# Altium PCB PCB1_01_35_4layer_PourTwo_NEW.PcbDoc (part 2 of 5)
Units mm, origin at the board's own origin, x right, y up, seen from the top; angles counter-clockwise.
Board outline 26.5 x 17 mm, 4 copper layers (Top Layer, Layer 1, Layer 2, Bottom Layer), stack 0.603 mm thick; 0 components, 1 nets, 8 pads, 81 vias.

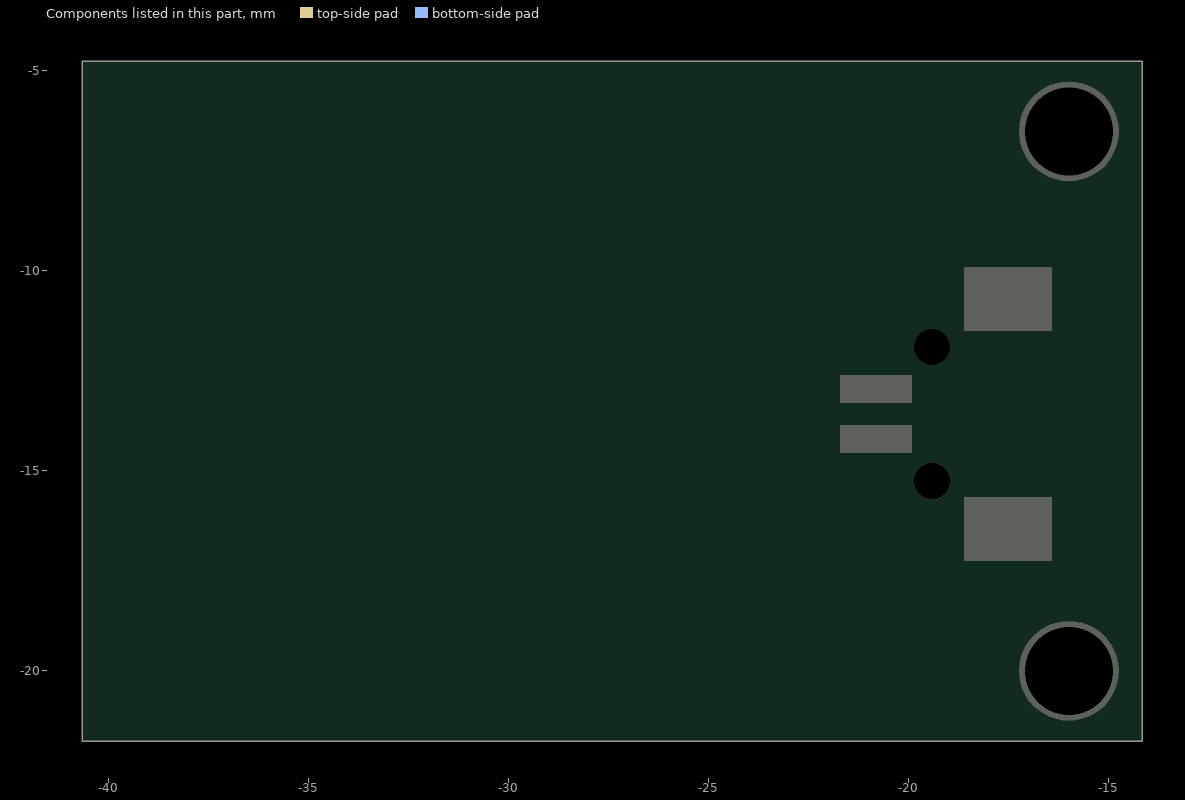
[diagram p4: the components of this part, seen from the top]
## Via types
v1: diameter 0.5, hole 0.3, Top Layer to Bottom Layer, tented both sides, 68 vias
v2: diameter 1, hole 0.5, Top Layer to Bottom Layer, 9 vias
v3: diameter 0.65, hole 0.3, Top Layer to Bottom Layer, 4 vias

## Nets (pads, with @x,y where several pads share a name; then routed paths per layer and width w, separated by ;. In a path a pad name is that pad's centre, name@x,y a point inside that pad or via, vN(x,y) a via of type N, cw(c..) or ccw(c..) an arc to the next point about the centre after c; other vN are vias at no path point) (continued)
copper on no net: | length 3951.7
  Top Layer w0.1: v3(-32.113,-13.739) -32.133,-13.739 -32.71,-13.162 -32.942,-13.162 cw(c-31.927,-13.291) -32.883,-12.927 cw(c-31.835,-13.326) -32.772,-12.709 cw(c-31.779,-13.362) -32.616,-12.519 cw(c-31.776,-13.364) -32.423,-12.364 cw(c-31.806,-13.316) -32.202,-12.252 cw(c-31.832,-13.244) -31.959,-12.193 cw(c-31.832,-13.275) -31.707,-12.193 cw(c-31.843,-13.372) -31.46,-12.249 cw(c-31.859,-13.422) -31.228,-12.355 cw(c-31.849,-13.408) -31.022,-12.508 cw(c-31.802,-13.357) -30.853,-12.702 cw(c-31.77,-13.33) -30.668,-13.185 cw(c-31.907,-13.355) -30.66,-13.448 cw(c-31.926,-13.356) -30.807,-13.954 cw(c-31.835,-13.402) -30.959,-14.173 cw(c-31.801,-13.43) -31.159,-14.352 cw(c-31.861,-13.344) -31.396,-14.481 cw(c-31.892,-13.269) -31.658,-14.557 cw(c-31.896,-13.256) -31.93,-14.578 cw(c-31.898,-13.312) -32.202,-14.541 cw(c-31.919,-13.395) -32.46,-14.444 cw(c-31.912,-13.391) -32.69,-14.288 cw(c-31.841,-13.308) -32.88,-14.084 cw(c-31.789,-13.267) -33.025,-13.842 cw(c-31.797,-13.27) -33.117,-13.575 cw(c-31.868,-13.286) -33.15,-13.293 cw(c-31.954,-13.287) -33.117,-13.01 cw(c-31.893,-13.304) -33.019,-12.741 cw(c-31.799,-13.35) -32.863,-12.497 cw(c-31.769,-13.371) -32.416,-12.129 cw(c-31.819,-13.278) -32.143,-12.025 cw(c-31.838,-13.213) -31.851,-11.986 cw(c-31.837,-13.318) -31.556,-12.016 cw(c-31.856,-13.412) -31.273,-12.109 cw(c-31.865,-13.435) -31.013,-12.259 cw(c-31.834,-13.392) -30.79,-12.46 cw(c-31.763,-13.33) -30.617,-12.706 cw(c-31.747,-13.317) -30.505,-12.989 cw(c-31.863,-13.348) -30.459,-13.291 cw(c-31.943,-13.352) -30.478,-13.598 cw(c-31.945,-13.353) -30.56,-13.895 cw(c-31.877,-13.38) -30.704,-14.169 cw(c-31.796,-13.435) -30.907,-14.405 cw(c-31.821,-13.402) -31.161,-14.588 cw(c-31.879,-13.299) -31.451,-14.711 cw(c-31.898,-13.24) -31.762,-14.771 cw(c-31.897,-13.264) -32.079,-14.767 cw(c-31.908,-13.352) -32.389,-14.693 cw(c-31.92,-13.4) -32.922,-14.342 cw(c-31.803,-13.28) -33.119,-14.085 cw(c-31.789,-13.267) -33.337,-13.474 cw(c-31.917,-13.286) -33.343,-13.146 cw(c-31.967,-13.284) -33.271,-12.824 cw(c-31.848,-13.326) -33.127,-12.526 cw(c-31.765,-13.377) -32.922,-12.263 cw(c-31.755,-13.385) -32.666,-12.047 cw(c-31.794,-13.326) -32.37,-11.889 cw(c-31.834,-13.225) -32.044,-11.801 cw(c-31.837,-13.24) -31.706,-11.792 cw(c-31.848,-13.37) -31.372,-11.859 cw(c-31.87,-13.444) -31.057,-11.995 cw(c-31.862,-13.432) -30.776,-12.194 cw(c-31.802,-13.365) -30.544,-12.448 cw(c-31.716,-13.302) -30.375,-12.75 cw(c-31.792,-13.33) -30.28,-13.085 cw(c-31.915,-13.35) -30.261,-13.435 cw(c-31.953,-13.351) -30.44,-14.113 cw(c-31.835,-13.409) -30.634,-14.408 cw(c-31.773,-13.458) -30.893,-14.652 cw(c-31.848,-13.355) -31.202,-14.831 cw(c-31.894,-13.253) -31.545,-14.94 cw(c-31.9,-13.227) -31.904,-14.976 cw(c-31.902,-13.294) -32.263,-14.937 cw(c-31.927,-13.407) -32.606,-14.818 cw(c-31.931,-13.426) -32.914,-14.622 cw(c-31.842,-13.316) -33.17,-14.36 cw(c-31.769,-13.258) -33.367,-14.048 cw(c-31.771,-13.257) -33.496,-13.701 cw(c-31.858,-13.279) -33.548,-13.334 cw(c-31.978,-13.282) -33.516,-12.963 cw(c-31.924,-13.298) -33.398,-12.608 cw(c-31.799,-13.356) -33.203,-12.287 cw(c-31.742,-13.398) -32.944,-12.011 cw(c-31.762,-13.373) -32.634,-11.794 cw(c-31.814,-13.277) -32.283,-11.649 cw(c-31.836,-13.227) -31.524,-11.616 cw(c-31.863,-13.421) -31.155,-11.727 cw(c-31.867,-13.439) -30.52,-12.164 cw(c-31.754,-13.329) -30.287,-12.476 cw(c-31.709,-13.298) -30.133,-12.835 cw(c-31.852,-13.34) -30.065,-13.222 cw(c-31.962,-13.349) -30.079,-13.616 cw(c-31.974,-13.348) -30.175,-14.001 cw(c-31.893,-13.379) -30.349,-14.357 cw(c-31.784,-13.449) -30.601,-14.666 cw(c-31.795,-13.429) -30.919,-14.909 cw(c-31.873,-13.299) -31.284,-15.075 cw(c-31.902,-13.216) -31.679,-15.162 cw(c-31.901,-13.236) -32.084,-15.167 cw(c-31.913,-13.345) -32.481,-15.084 cw(c-31.951,-13.464) -32.851,-14.912 cw(c-31.896,-13.381) -33.171,-14.657 cw(c-31.795,-13.279) -33.43,-14.338 cw(c-31.763,-13.254) -33.726,-13.57 cw(c-31.92,-13.282) -33.745,-13.156 cw(c-32.009,-13.278) -33.666,-12.746 cw(c-31.866,-13.324) -33.494,-12.364 cw(c-31.755,-13.388) -33.244,-12.026 cw(c-31.734,-13.406) -32.929,-11.745 cw(c-31.78,-13.339) -32.561,-11.536 cw(c-31.834,-13.213) -32.155,-11.414 cw(c-31.842,-13.198) -31.729,-11.39 cw(c-31.852,-13.361) -31.308,-11.463 cw(c-31.88,-13.463) -30.909,-11.623 cw(c-31.876,-13.459) -30.55,-11.863 cw(c-31.806,-13.377) -30.25,-12.174 cw(c-31.695,-13.291) -30.027,-12.546 cw(c-31.762,-13.315) -29.898,-12.961 cw(c-31.917,-13.346) -29.862,-13.397 cw(c-31.982,-13.347) -30.063,-14.249 cw(c-31.84,-13.412) -30.294,-14.624 cw(c-31.788,-13.441) -30.986,-15.17 cw(c-31.893,-13.242) -31.408,-15.317 cw(c-31.902,-13.228) -32.3,-15.337 cw(c-31.933,-13.412) -32.729,-15.202 cw(c-31.931,-13.423) -33.118,-14.97 cw(c-31.839,-13.302) -33.447,-14.656 cw(c-31.796,-13.262) -33.874,-13.854 cw(c-31.942,-13.305) -33.949,-13.401 cw(c-31.932,-13.311) -33.917,-12.941 cw(c-31.792,-13.336) -33.784,-12.498 cw(c-31.768,-13.341) -33.255,-11.74 cw(c-31.888,-13.218) -32.879,-11.465 cw(c-31.856,-13.283) -32.447,-11.283 cw(c-31.818,-13.407) -31.985,-11.198 cw(c-31.815,-13.433) -31.513,-11.212 cw(c-31.802,-13.347) -31.055,-11.326 cw(c-31.781,-13.274) -30.268,-11.848 cw(c-31.91,-13.409) -29.977,-12.228 cw(c-31.91,-13.411) -29.772,-12.661 cw(c-31.809,-13.377) -29.664,-13.129 cw(c-31.714,-13.363) -29.665,-13.611 cw(c-31.866,-13.345) -29.775,-14.082 cw(c-31.956,-13.315) -29.984,-14.52 cw(c-31.934,-13.329) -30.281,-14.907 cw(c-31.846,-13.415) -30.655,-15.219 cw(c-31.819,-13.447) -31.092,-15.439 cw(c-31.874,-13.298) -31.57,-15.557 cw(c-31.884,-13.246) -32.549,-15.482 cw(c-31.93,-13.41) -33.005,-15.286 cw(c-31.912,-13.39) -33.405,-14.991 cw(c-31.811,-13.28) -33.731,-14.613 cw(c-31.801,-13.267) -34.116,-13.693 cw(c-31.985,-13.305) -34.148,-13.191 cw(c-31.893,-13.314) -34.064,-12.693 cw(c-31.763,-13.35) -33.874,-12.223 cw(c-31.744,-13.358) -33.588,-11.801 cw(c-31.819,-13.293) -33.219,-11.451 cw(c-31.867,-13.243) -32.289,-11.038 cw(c-31.819,-13.435) -31.776,-10.993 cw(c-31.817,-13.428) -31.264,-11.056 cw(c-31.789,-13.312) -30.777,-11.228 cw(c-31.752,-13.229) -30.34,-11.508 cw(c-31.858,-13.358) -29.976,-11.88 cw(c-31.932,-13.418) -29.698,-12.323 cw(c-31.9,-13.404) -29.519,-12.815 cw(c-31.767,-13.373) -29.451,-13.335 cw(c-31.739,-13.366) -29.504,-13.859 cw(c-31.903,-13.331) -29.673,-14.36 cw(c-31.947,-13.315) -30.305,-15.204 cw(c-31.821,-13.456) -30.745,-15.505 cw(c-31.836,-13.412) -31.244,-15.696 cw(c-31.877,-13.262) -31.774,-15.775 cw(c-31.881,-13.218) -32.311,-15.741 cw(c-31.897,-13.305) -32.829,-15.594 cw(c-31.955,-13.447) -33.302,-15.333 cw(c-31.886,-13.357) -33.704,-14.97 cw(c-31.782,-13.263) -34.021,-14.528 cw(c-31.77,-13.254) -34.238,-14.027 cw(c-31.878,-13.286) -34.343,-13.491 cw(c-31.937,-13.301) -34.181,-12.413 cw(c-31.74,-13.366) -33.927,-11.923 cw(c-31.751,-13.356) -33.576,-11.496 cw(c-31.843,-13.261) -33.14,-11.155 cw(c-31.891,-13.192) -32.635,-10.922 cw(c-31.834,-13.362) -32.09,-10.806 cw(c-31.823,-13.457) -31.531,-10.809 cw(c-31.816,-13.413) -30.983,-10.929 cw(c-31.767,-13.271) -30.475,-11.167 cw(c-31.767,-13.257) -30.033,-11.516 cw(c-31.89,-13.383) -29.677,-11.955 cw(c-31.921,-13.408) -29.278,-13.011 cw(c-31.716,-13.374) -29.259,-13.58 cw(c-31.782,-13.362) -29.372,-14.139 cw(c-31.936,-13.313) -29.605,-14.663 cw(c-31.971,-13.296) -29.943,-15.128 cw(c-31.897,-13.364) -30.373,-15.51 cw(c-31.804,-13.496) -30.88,-15.787 cw(c-31.851,-13.37) -31.437,-15.942 cw(c-31.876,-13.228) -32.017,-15.973 cw(c-31.877,-13.22) -32.592,-15.883 cw(c-31.911,-13.341) -33.135,-15.67 cw(c-31.971,-13.459) -33.617,-15.339 cw(c-31.853,-13.325) -34.013,-14.907 cw(c-31.756,-13.252) -34.309,-14.398 cw(c-31.779,-13.26) -34.493,-13.838 cw(c-31.923,-13.29) -34.55,-13.25 cw(c-31.995,-13.294) -34.471,-12.663 cw(c-31.81,-13.34) -34.263,-12.106 cw(c-31.74,-13.371) -33.52,-11.181 cw(c-31.869,-13.217) -33.016,-10.859 cw(c-31.873,-13.227) -32.449,-10.662 cw(c-31.831,-13.405) -31.851,-10.593 cw(c-31.825,-13.435) -30.674,-10.837 cw(c-31.738,-13.227) -30.152,-11.146 cw(c-31.797,-13.294) -29.714,-11.567 cw(c-31.924,-13.402) -29.377,-12.075 cw(c-31.953,-13.419) -29.153,-12.644 cw(c-31.843,-13.39) -29.054,-13.248 ; -29.056,-16.506 ccw(c-31.858,-13.398) -28.441,-15.813 ccw(c-31.984,-13.306) -27.99,-15.006 ccw(c-31.93,-13.326) -27.722,-14.122 ccw(c-31.697,-13.368) -27.654,-13.203 ccw(c-31.802,-13.38) -27.795,-12.294 ccw(c-31.956,-13.419) -28.128,-11.438 ccw(c-31.911,-13.393) -28.634,-10.673 ccw(c-31.732,-13.242) -29.294,-10.039 ccw(c-31.782,-13.321) -30.079,-9.572 ccw(c-31.851,-13.467) -30.945,-9.284 ccw(c-31.845,-13.421) -31.851,-9.188 ccw(c-31.847,-13.186) -32.754,-9.292 ccw(c-31.83,-13.207) -33.607,-9.598 ccw(c-31.729,-13.418) -34.373,-10.082 ccw(c-31.702,-13.457) -35.019,-10.715 ccw(c-31.839,-13.347) -35.515,-11.469 ccw(c-32.084,-13.222) -35.828,-12.313 ccw(c-31.893,-13.263) -35.941,-13.205 ccw(c-31.691,-13.268) -35.86,-14.099 ccw(c-31.692,-13.272) -35.593,-14.956 ccw(c-31.885,-13.358) -35.15,-15.733 ccw(c-32.065,-13.483) -34.543,-16.388 ccw(c-31.903,-13.292) -33.806,-16.889 ccw(c-31.823,-13.147) -32.979,-17.221 ccw(c-31.833,-13.196) -32.103,-17.372 ccw(c-31.847,-13.437) -31.218,-17.33 ccw(c-31.837,-13.556) -30.367,-17.086 ccw(c-31.972,-13.25) -28.926,-16.081 ccw(c-31.932,-13.276) -28.397,-15.376 ccw(c-31.704,-13.409) -28.037,-14.574 ccw(c-31.708,-13.42) -27.871,-13.713 ccw(c-32.004,-13.401) -28.108,-11.987 ccw(c-31.9,-13.358) -28.492,-11.202 ccw(c-31.668,-13.209) -29.04,-10.525 ccw(c-31.743,-13.299) -29.727,-9.992 ccw(c-31.859,-13.483) -30.512,-9.62 ccw(c-31.873,-13.514) -31.357,-9.422 ccw(c-31.853,-13.338) -32.222,-9.408 ccw(c-31.876,-13.083) -33.067,-9.589 ccw(c-31.807,-13.275) -33.847,-9.956 ccw(c-31.711,-13.435) -34.529,-10.482 ccw(c-31.723,-13.427) -35.086,-11.138 ccw(c-31.899,-13.31) -35.487,-11.896 ccw(c-32.074,-13.236) -35.705,-12.724 ccw(c-31.83,-13.27) -35.731,-13.578 ccw(c-31.681,-13.261) -35.576,-14.417 ccw(c-31.736,-13.281) -35.248,-15.204 ccw(c-31.945,-13.397) -34.759,-15.899 ccw(c-32.017,-13.448) -34.124,-16.462 ccw(c-31.842,-13.188) -32.571,-17.112 ccw(c-31.846,-13.248) -31.729,-17.177 ccw(c-31.836,-13.507) -30.895,-17.056 ccw(c-31.854,-13.482) -30.113,-16.748 ccw(c-31.96,-13.28) -29.419,-16.276 ccw(c-32,-13.228) -28.839,-15.67 ccw(c-31.885,-13.313) -28.402,-14.957 ccw(c-31.646,-13.425) -28.136,-14.166 ccw(c-31.78,-13.404) -28.058,-13.337 ccw(c-31.982,-13.405) -28.16,-12.511 ccw(c-32.003,-13.408) -28.433,-11.726 ccw(c-31.732,-13.261) -29.447,-10.43 ccw(c-31.785,-13.351) -30.144,-9.989 ccw(c-31.862,-13.503) -30.919,-9.707 ccw(c-31.859,-13.48) -31.734,-9.593 ccw(c-31.854,-13.27) -32.552,-9.658 ccw(c-31.879,-13.11) -33.333,-9.907 ccw(c-31.741,-13.395) -34.635,-10.881 ccw(c-31.755,-13.395) -35.102,-11.549 ccw(c-31.961,-13.283) -35.412,-12.3 ccw(c-32.014,-13.258) -35.541,-13.102 ccw(c-31.722,-13.266) -35.27,-14.689 ccw(c-31.787,-13.298) -34.891,-15.403 ccw(c-31.995,-13.441) -34.366,-16.013 ccw(c-31.965,-13.395) -33.716,-16.486 ccw(c-31.859,-13.211) -32.979,-16.805 ccw(c-31.841,-13.161) -32.193,-16.962 ccw(c-31.852,-13.307) -31.393,-16.95 ccw(c-31.82,-13.555) -30.618,-16.758 ccw(c-31.878,-13.417) -29.91,-16.396 ccw(c-31.979,-13.26) -29.296,-15.891 ccw(c-31.984,-13.251) -28.802,-15.268 ccw(c-31.722,-13.399) -28.277,-13.787 ccw(c-31.842,-13.398) -28.278,-12.999 ccw(c-31.996,-13.413) -28.447,-12.229 ccw(c-31.966,-13.4) -28.773,-11.514 ccw(c-31.788,-13.292) -29.244,-10.887 ccw(c-31.687,-13.206) -29.845,-10.386 ccw(c-31.845,-13.46) -31.296,-9.834 ccw(c-31.849,-13.435) -32.074,-9.799 ccw(c-31.865,-13.206) -32.839,-9.935 ccw(c-31.864,-13.174) -33.55,-10.241 ccw(c-31.725,-13.407) -34.691,-11.272 ccw(c-31.797,-13.362) -35.072,-11.942 ccw(c-32.02,-13.267) -35.294,-12.678 ccw(c-31.945,-13.272) -35.342,-13.443 ccw(c-31.748,-13.263) -35.223,-14.2 ccw(c-31.708,-13.255) -34.948,-14.914 ccw(c-31.838,-13.325) -34.528,-15.551 ccw(c-32.019,-13.474) -33.978,-16.077 ccw(c-31.926,-13.343) -33.324,-16.462 ccw(c-31.854,-13.188) -32.603,-16.698 ccw(c-31.852,-13.189) -31.85,-16.778 ccw(c-31.849,-13.368) -31.099,-16.694 ccw(c-31.811,-13.552) -30.389,-16.443 ccw(c-31.904,-13.365) -29.755,-16.039 ccw(c-31.99,-13.255) -29.222,-15.51 ccw(c-31.956,-13.279) -28.813,-14.882 ccw(c-31.774,-13.37) -28.55,-14.182 ccw(c-31.674,-13.403) -28.454,-13.443 ccw(c-31.954,-13.405) -28.752,-11.994 ccw(c-31.923,-13.384) -29.12,-11.35 ccw(c-31.742,-13.251) -29.62,-10.805 ccw(c-31.732,-13.254) -30.23,-10.39 ccw(c-31.845,-13.476) -31.641,-9.999 ccw(c-31.844,-13.383) -32.374,-10.034 ccw(c-31.882,-13.152) -33.079,-10.232 ccw(c-31.84,-13.236) -33.718,-10.584 ccw(c-31.736,-13.386) -34.266,-11.066 ccw(c-31.716,-13.408) -34.699,-11.651 ccw(c-31.846,-13.334) -34.997,-12.313 ccw(c-32.052,-13.266) -35.138,-13.024 ccw(c-31.885,-13.276) -35.114,-13.746 ccw(c-31.73,-13.256) -34.936,-14.445 ccw(c-31.739,-13.262) -34.615,-15.091 ccw(c-31.887,-13.359) -34.166,-15.65 ccw(c-32.005,-13.471) -33.601,-16.092 ccw(c-31.899,-13.297) -32.954,-16.395 ccw(c-31.857,-13.179) -32.257,-16.553 ccw(c-31.86,-13.228) -31.545,-16.562 ccw(c-31.839,-13.427) -30.849,-16.416 ccw(c-31.823,-13.503) -30.207,-16.116 ccw(c-31.964,-13.284) -29.196,-15.139 ccw(c-31.92,-13.307) -28.868,-14.515 ccw(c-31.717,-13.385) -28.685,-13.836 ccw(c-31.737,-13.391) -28.663,-13.136 ccw(c-31.926,-13.405) -28.795,-12.448 ccw(c-31.98,-13.419) -29.068,-11.805 ccw(c-31.877,-13.36) -29.47,-11.235 ccw(c-31.711,-13.212) -29.987,-10.771 ccw(c-31.769,-13.305) -30.595,-10.438 ccw(c-31.834,-13.459) -31.26,-10.245 ccw(c-31.84,-13.477) -31.95,-10.195 ccw(c-31.862,-13.22) -33.273,-10.543 ccw(c-31.813,-13.286) -33.839,-10.929 ccw(c-31.723,-13.394) -34.309,-11.428 ccw(c-31.739,-13.385) -34.663,-12.013 ccw(c-31.898,-13.312) -34.882,-12.658 ccw(c-32.032,-13.278) -34.948,-13.334 ccw(c-31.836,-13.274) -34.862,-14.007 ccw(c-31.727,-13.25) -34.634,-14.645 ccw(c-31.776,-13.276) -34.279,-15.22 ccw(c-31.929,-13.397) -33.809,-15.702 ccw(c-31.968,-13.432) -33.241,-16.062 ccw(c-31.867,-13.214) -31.946,-16.376 ccw(c-31.863,-13.274) -31.28,-16.322 ccw(c-31.823,-13.479) -30.645,-16.122 ccw(c-31.846,-13.446) -30.073,-15.783 ccw(c-31.951,-13.306) -29.59,-15.329 ccw(c-31.983,-13.275) -29.214,-14.784 ccw(c-31.876,-13.331) -28.963,-14.173 ccw(c-31.675,-13.389) -28.855,-13.524 ccw(c-31.795,-13.388) -28.898,-12.869 ccw(c-31.946,-13.413) -29.081,-12.239 ccw(c-31.955,-13.414) -29.391,-11.663 ccw(c-31.757,-13.263) -30.341,-10.783 ccw(c-31.795,-13.35) -30.937,-10.527 ccw(c-31.833,-13.471) -31.573,-10.404 ccw(c-31.833,-13.444) -32.22,-10.418 ccw(c-31.857,-13.275) -32.846,-10.57 ccw(c-31.89,-13.166) -33.42,-10.861 ccw(c-31.751,-13.366) -34.307,-11.776 ccw(c-31.771,-13.361) -34.586,-12.351 ccw(c-31.95,-13.299) -34.732,-12.971 ccw(c-31.977,-13.287) -34.731,-13.606 ccw(c-31.759,-13.259) -34.325,-14.799 ccw(c-31.815,-13.298) -33.944,-15.302 ccw(c-31.96,-13.436) -33.463,-15.708 ccw(c-31.934,-13.384) -32.904,-15.991 ccw(c-31.877,-13.234) -32.297,-16.146 ccw(c-31.87,-13.201) -31.672,-16.17 ccw(c-31.86,-13.322) -31.058,-16.061 ccw(c-31.806,-13.508) -30.486,-15.818 ccw(c-31.872,-13.399) -29.986,-15.452 ccw(c-31.965,-13.296) -29.577,-14.988 ccw(c-31.964,-13.294) -29.274,-14.449 ccw(c-31.74,-13.377) -29.054,-13.248 ; -29.056,-16.506 cw(c-31.775,-13.48) -29.812,-17.043 cw(c-31.892,-13.271) -30.669,-17.401 cw(c-31.913,-13.211) -31.585,-17.57 cw(c-31.904,-13.363) -32.516,-17.537 cw(c-31.916,-13.491) -33.418,-17.296 cw(c-31.829,-13.265) -34.246,-16.861 cw(c-31.793,-13.207) -34.965,-16.258 cw(c-31.902,-13.308) -35.537,-15.515 cw(c-32.018,-13.386) -35.928,-14.66 cw(c-31.786,-13.309) -36.122,-13.739 cw(c-31.775,-13.298) -35.906,-11.875 cw(c-32.001,-13.235) -35.495,-11.023 cw(c-31.793,-13.366) -34.904,-10.281 cw(c-31.771,-13.373) -33.32,-9.253 cw(c-31.87,-13.15) -32.395,-9.025 cw(c-31.838,-13.395) -31.442,-9.008 cw(c-31.831,-13.424) -29.628,-9.577 cw(c-31.717,-13.199) -28.858,-10.148 cw(c-31.886,-13.38) -28.233,-10.876 cw(c-31.911,-13.408) -27.51,-12.648 cw(c-31.656,-13.352) -27.459,-13.611 cw(c-31.903,-13.337) -27.623,-14.563 cw(c-31.949,-13.333) -28.534,-16.26 cw(c-31.738,-13.499) -29.247,-16.917 cw(c-31.883,-13.3) -30.091,-17.401 cw(c-31.912,-13.254) -31.991,-17.783 cw(c-31.906,-13.53) -32.958,-17.651 cw(c-31.845,-13.292) -33.874,-17.308 cw(c-31.825,-13.233) -35.389,-16.079 cw(c-31.94,-13.355) -36.229,-14.314 cw(c-31.752,-13.29) -36.248,-12.352 cw(c-31.928,-13.276) -35.418,-10.568 cw(c-31.751,-13.385) -33.909,-9.295 cw(c-31.856,-13.233) -31.994,-8.795 cw(c-31.827,-13.447) -30.039,-9.149 cw(c-31.772,-13.261) -28.422,-10.312 cw(c-31.925,-13.426) -27.443,-12.055 cw(c-31.738,-13.349) -27.308,-14.054 cw(c-31.971,-13.334) -28.032,-15.931 cw(c-31.787,-13.434) -29.495,-17.317 cw(c-31.927,-13.239) -31.414,-17.96 cw(c-31.888,-13.541) -32.434,-17.951 cw(c-31.858,-13.329) -33.427,-17.715 cw(c-31.823,-13.212) -35.155,-16.639 cw(c-32.032,-13.435) -35.803,-15.843 cw(c-31.856,-13.328) -36.257,-14.922 cw(c-31.735,-13.278) -36.531,-12.892 cw(c-32.041,-13.258) -36.329,-11.88 cw(c-31.854,-13.324) -35.906,-10.937 cw(c-31.731,-13.39) -34.508,-9.424 cw(c-31.911,-13.141) -33.595,-8.93 cw(c-31.846,-13.319) -32.593,-8.654 cw(c-31.816,-13.487) -31.552,-8.599 cw(c-31.809,-13.412) -30.523,-8.767 cw(c-31.74,-13.168) -29.555,-9.159 cw(c-31.832,-13.323) -28.698,-9.759 cw(c-31.946,-13.457) -27.989,-10.53 cw(c-31.888,-13.419) -27.459,-11.435 cw(c-31.655,-13.316) -27.142,-12.437 cw(c-31.822,-13.341) -27.058,-13.485 cw(c-32.005,-13.339) -27.201,-14.529 cw(c-31.944,-13.357) -27.563,-15.52 cw(c-31.715,-13.472) -28.135,-16.408 cw(c-31.833,-13.365) -28.894,-17.146 cw(c-31.951,-13.218) -29.795,-17.704 cw(c-31.929,-13.273) -30.795,-18.059 cw(c-31.872,-13.522) -31.85,-18.185 cw(c-31.863,-13.375) -32.908,-18.07 cw(c-31.824,-13.184) -33.919,-17.729 cw(c-31.849,-13.231) -34.835,-17.181 cw(c-32.005,-13.434) -35.609,-16.444 cw(c-31.896,-13.355) -36.198,-15.551 cw(c-31.718,-13.26) -36.582,-14.549 cw(c-31.765,-13.269) -36.744,-13.488 cw(c-32.02,-13.278) -36.669,-12.416 cw(c-31.902,-13.31) -36.355,-11.387 cw(c-31.71,-13.39) -35.825,-10.447 cw(c-31.742,-13.363) -35.106,-9.641 cw(c-31.911,-13.172) -34.228,-9.011 cw(c-31.867,-13.273) -33.228,-8.595 cw(c-31.804,-13.477) -32.16,-8.404 cw(c-31.803,-13.441) -31.075,-8.444 cw(c-31.764,-13.191) -30.024,-8.722 cw(c-31.809,-13.276) -29.061,-9.229 cw(c-31.93,-13.46) -28.229,-9.934 cw(c-31.906,-13.442) -27.564,-10.801 cw(c-31.69,-13.313) -27.105,-11.793 cw(c-31.771,-13.328) -26.881,-12.865 cw(c-31.996,-13.352) -26.894,-13.962 cw(c-31.973,-13.359) -27.14,-15.032 cw(c-31.738,-13.443) -27.614,-16.024 cw(c-31.789,-13.397) -28.3,-16.884 cw(c-31.955,-13.235) -29.159,-17.577 cw(c-31.949,-13.252) -30.146,-18.073 cw(c-31.864,-13.484) -31.218,-18.341 cw(c-31.859,-13.43) -32.325,-18.361 cw(c-31.84,-13.193) -33.412,-18.14 cw(c-31.847,-13.203) -34.429,-17.692 cw(c-31.971,-13.414) -35.324,-17.034 cw(c-31.936,-13.394) -36.049,-16.189 cw(c-31.736,-13.255) -36.574,-15.205 cw(c-31.742,-13.253) -36.879,-14.13 cw(c-31.981,-13.291) -36.943,-13.015 cw(c-31.959,-13.305) -36.753,-11.912 cw(c-31.718,-13.372) -36.327,-10.874 cw(c-31.715,-13.37) -35.69,-9.949 cw(c-31.895,-13.211) -34.866,-9.185 cw(c-31.9,-13.225) -33.89,-8.625 cw(c-31.796,-13.458) -32.813,-8.29 cw(c-31.791,-13.466) -31.688,-8.191 cw(c-31.783,-13.229) -30.568,-8.339 cw(c-31.794,-13.219) -29.508,-8.737 cw(c-31.91,-13.453) -28.559,-9.356 cw(c-31.917,-13.467) -27.762,-10.164 cw(c-31.732,-13.324) -27.158,-11.127 cw(c-31.717,-13.302) -26.787,-12.202 cw(c-31.976,-13.363) -26.659,-13.335 cw(c-31.998,-13.367) -26.774,-14.471 cw(c-31.774,-13.417) -27.133,-15.555 cw(c-31.733,-13.422) -27.728,-16.532 cw(c-31.95,-13.258) -28.523,-17.357 cw(c-31.971,-13.238) -29.477,-17.995 cw(c-31.868,-13.44) -30.547,-18.412 cw(c-31.842,-13.49) -31.685,-18.577 cw(c-31.854,-13.213) -32.834,-18.49 cw(c-31.851,-13.178) -33.94,-18.16 cw(c-31.94,-13.382) -34.948,-17.598 cw(c-31.971,-13.446) -35.806,-16.823 cw(c-31.761,-13.257) -36.474,-15.877 cw(c-31.726,-13.233) -36.927,-14.809 cw(c-31.937,-13.294) -37.138,-13.668 cw(c-32.022,-13.312) -37.087,-12.506 cw(c-31.737,-13.354) -36.782,-11.383 cw(c-31.69,-13.368) -36.245,-10.348 cw(c-31.868,-13.247) -35.496,-9.453 cw(c-31.947,-13.181) -34.564,-8.748 cw(c-31.795,-13.431) -33.498,-8.264 cw(c-31.774,-13.483) -32.352,-8.017 cw(c-31.793,-13.273) -31.18,-8.023 cw(c-31.79,-13.155) -30.036,-8.294 cw(c-31.888,-13.435) -28.979,-8.81 cw(c-31.919,-13.49) -28.053,-9.539 cw(c-31.771,-13.344) -27.307,-10.451 cw(c-31.666,-13.264) -26.784,-11.51 cw(c-31.948,-13.368) -26.505,-12.66 cw(c-32.016,-13.381) -26.478,-13.844 cw(c-31.814,-13.401) -26.706,-15.007 cw(c-31.671,-13.436) -27.19,-16.09 cw(c-31.934,-13.283) -27.903,-17.042 cw(c-31.993,-13.234) -28.802,-17.822 cw(c-31.882,-13.399) -29.849,-18.391 cw(c-31.813,-13.545) -30.999,-18.71 cw(c-31.863,-13.242) -32.192,-18.768 cw(c-31.862,-13.158) -33.373,-18.571 cw(c-31.917,-13.344) -34.484,-18.124 cw(c-31.994,-13.503) -35.468,-17.439 cw(c-31.79,-13.27) -36.277,-16.551 cw(c-31.789,-13.253) -37.247,-14.364 cw(c-32.078,-13.332) -37.346,-13.163 cw(c-31.767,-13.34) -37.178,-11.968 cw(c-31.744,-13.333) -36.105,-9.815 cw(c-31.997,-13.152) -35.238,-8.969 cw(c-31.804,-13.398) -34.204,-8.333 cw(c-31.78,-13.421) -31.85,-7.786 cw(c-31.801,-13.1) -30.639,-7.914 cw(c-31.868,-13.406) -29.485,-8.308 cw(c-31.875,-13.448) -27.553,-9.78 cw(c-31.633,-13.221) -26.877,-10.8 cw(c-31.911,-13.364) -26.442,-11.946 cw(c-31.958,-13.388) -26.345,-14.386 cw(c-31.62,-13.433) -26.701,-15.563 cw(c-31.906,-13.309) -27.31,-16.633 cw(c-31.963,-13.282) -29.137,-18.271 cw(c-31.778,-13.579) -30.277,-18.75 cw(c-31.865,-13.282) -31.496,-18.964 cw(c-31.88,-13.21) -33.935,-18.598 cw(c-31.927,-13.418) -35.982,-17.215 cw(c-31.769,-13.231) -37.261,-15.092 cw(c-31.97,-13.329) -37.502,-12.622 cw(c-31.714,-13.333) -36.677,-10.272 cw(c-31.927,-13.235) -34.918,-8.502 cw(c-31.761,-13.443) -32.57,-7.636 cw(c-31.821,-13.206) -30.074,-7.864 cw(c-31.88,-13.476) -27.899,-9.128 cw(c-31.726,-13.272) -26.476,-11.207 cw(c-31.982,-13.403) -26.062,-13.7 cw(c-31.717,-13.393) -26.76,-16.133 cw(c-31.989,-13.274) -28.426,-18.05 cw(c-31.752,-13.578) -29.533,-18.691 cw(c-31.855,-13.329) -30.756,-19.068 cw(c-31.891,-13.186) -33.307,-19.007 cw(c-31.975,-13.563) -34.513,-18.56 cw(c-31.853,-13.334) -35.588,-17.854 cw(c-31.758,-13.207) -37.174,-15.839 cw(c-32.104,-13.382) -37.601,-14.621 cw(c-31.859,-13.333) -37.743,-13.336 cw(c-31.69,-13.326) -37.199,-10.817 cw(c-32.044,-13.171) -36.529,-9.707 cw(c-31.86,-13.322) -35.625,-8.774 cw(c-31.74,-13.456) -33.327,-7.582 cw(c-31.846,-13.085) -32.038,-7.39 cw(c-31.846,-13.311) -30.737,-7.491 cw(c-31.883,-13.525) -29.485,-7.871 cw(c-31.844,-13.444) -28.343,-8.508 cw(c-31.657,-13.184) -27.368,-9.383 cw(c-31.823,-13.318) -26.613,-10.455 cw(c-32.018,-13.43) -26.106,-11.667 cw(c-31.936,-13.41) -25.868,-12.959 cw(c-31.616,-13.388) -25.92,-14.274 cw(c-31.812,-13.348) -26.267,-15.545 cw(c-32.029,-13.266) -26.88,-16.714 cw(c-31.968,-13.312) -27.728,-17.726 cw(c-31.747,-13.546) -28.78,-18.527 cw(c-31.833,-13.381) -29.986,-19.073 cw(c-31.91,-13.155) -31.283,-19.346 cw(c-31.908,-13.224) -32.61,-19.338 cw(c-31.947,-13.543) -33.903,-19.037 cw(c-31.879,-13.386) -35.098,-18.453 cw(c-31.75,-13.176) -36.14,-17.624 cw(c-31.797,-13.217) -36.983,-16.591 cw(c-32.066,-13.389) -37.579,-15.398 cw(c-31.916,-13.348) -37.892,-14.099 cw(c-31.665,-13.312) -37.917,-12.761 cw(c-31.719,-13.303) -37.657,-11.447 cw(c-32.023,-13.205) -37.116,-10.221 cw(c-31.91,-13.287) -36.311,-9.148 cw(c-31.717,-13.463) -35.291,-8.272 cw(c-31.74,-13.421) -34.108,-7.632 cw(c-31.857,-13.127) -32.812,-7.266 cw(c-31.851,-13.249) -31.466,-7.201 cw(c-31.864,-13.517) -30.135,-7.43 cw(c-31.849,-13.48) -28.881,-7.936 cw(c-31.698,-13.204) -27.768,-8.705 cw(c-31.778,-13.274) -26.856,-9.705 cw(c-31.998,-13.439) -26.181,-10.882 cw(c-31.967,-13.43) -25.771,-12.176 cw(c-31.661,-13.371) -25.653,-13.53 cw(c-31.748,-13.354) -25.843,-14.877 cw(c-32.022,-13.287) -26.322,-16.152 cw(c-32.002,-13.302) -27.061,-17.299 cw(c-31.764,-13.499) -28.033,-18.257 cw(c-31.795,-13.435) -29.197,-18.972 cw(c-31.921,-13.174) -30.491,-19.418 cw(c-31.922,-13.192) -31.852,-19.58 cw(c-31.922,-13.498) -33.216,-19.441 cw(c-31.896,-13.451) -34.514,-18.998 cw(c-31.773,-13.181) -35.688,-18.282 cw(c-31.782,-13.186) -36.685,-17.333 cw(c-32.014,-13.378) -37.451,-16.188 cw(c-31.979,-13.377) -37.939,-14.899 cw(c-31.685,-13.298) -38.137,-13.532 cw(c-31.687,-13.294) -38.039,-12.153 cw(c-31.979,-13.238) -37.644,-10.828 cw(c-31.973,-13.258) -36.96,-9.624 cw(c-31.72,-13.438) -36.028,-8.596 cw(c-31.712,-13.439) -34.898,-7.789 cw(c-31.853,-13.182) -33.62,-7.246 cw(c-31.87,-13.181) -32.25,-7.005 cw(c-31.847,-13.498) -30.858,-7.068 cw(c-31.845,-13.513) -29.51,-7.426 cw(c-31.738,-13.243) -28.271,-8.067 cw(c-31.737,-13.214) -27.207,-8.973 cw(c-31.971,-13.438) -26.365,-10.091 cw(c-31.988,-13.454) -25.779,-11.363 cw(c-31.717,-13.366) -25.482,-12.733 cw(c-31.674,-13.346) -25.502,-14.136 cw(c-32.003,-13.308) -25.828,-15.503 cw(c-32.034,-13.302) -26.438,-16.772 cw(c-31.797,-13.453) -27.308,-17.878 cw(c-31.741,-13.487) -28.406,-18.761 cw(c-31.924,-13.204) -29.673,-19.384 cw(c-31.942,-13.168) -31.045,-19.724 cw(c-31.908,-13.443) -32.458,-19.759 cw(c-31.901,-13.526) -33.845,-19.475 cw(c-31.797,-13.199) -35.137,-18.893 cw(c-31.777,-13.155) -36.279,-18.049 cw(c-31.964,-13.353) -37.211,-16.978 cw(c-32.04,-13.422) -37.878,-15.722 cw(c-31.716,-13.291) -38.256,-14.35 cw(c-31.662,-13.278) -38.333,-12.926 cw(c-31.928,-13.26) -38.101,-11.519 cw(c-32.048,-13.24) -37.557,-10.199 cw(c-31.735,-13.409) -36.736,-9.028 cw(c-31.684,-13.447) -35.684,-8.057 cw(c-31.837,-13.235) -34.447,-7.336 cw(c-31.905,-13.113) -33.077,-6.911 cw(c-31.835,-13.466) -31.645,-6.797 cw(c-31.832,-13.539) -30.22,-6.99 cw(c-31.767,-13.291) -28.87,-7.486 cw(c-31.708,-13.144) -27.665,-8.274 cw(c-31.938,-13.426) -26.66,-9.309 cw(c-31.999,-13.48) -25.898,-10.535 cw(c-31.772,-13.374) -25.417,-11.897 cw(c-31.603,-13.323) -25.255,-13.334 cw(c-31.971,-13.325) -25.413,-14.774 cw(c-32.06,-13.311) -25.873,-16.149 cw(c-31.839,-13.417) -26.62,-17.393 cw(c-31.678,-13.526) -27.628,-18.439 cw(c-31.916,-13.241) -28.843,-19.238 cw(c-31.965,-13.155) -30.202,-19.761 cw(c-31.908,-13.388) -31.642,-19.98 cw(c-31.889,-13.598) -33.096,-19.87 cw(c-31.821,-13.23) -34.493,-19.441 cw(c-31.783,-13.13) -35.767,-18.724 cw(c-31.922,-13.318) -36.859,-17.75 cw(c-32.085,-13.477) -37.704,-16.554 cw(c-31.756,-13.294) -38.266,-15.199 cw(c-31.741,-13.274) -38.472,-12.286 cw(c-32.116,-13.241) -38.089,-10.866 cw(c-31.765,-13.379) -37.4,-9.564 cw(c-31.73,-13.385) -35.277,-7.54 cw(c-31.95,-13.064) -33.933,-6.928 cw(c-31.832,-13.423) -32.485,-6.628 cw(c-31.813,-13.466) -29.56,-6.975 cw(c-31.701,-13.081) -28.226,-7.623 cw(c-31.903,-13.4) -27.067,-8.551 cw(c-31.933,-13.45) -25.464,-11.036 cw(c-31.553,-13.288) -25.111,-12.483 cw(c-31.927,-13.336) -25.088,-13.974 cw(c-31.997,-13.343) -25.984,-16.805 cw(c-31.622,-13.539) -26.878,-18.004 cw(c-31.894,-13.282) -28.016,-18.976 cw(c-31.951,-13.222) -30.781,-20.094 cw(c-31.872,-13.466) -33.761,-19.912 cw(c-31.825,-13.181) -36.395,-18.489 cw(c-31.972,-13.406) -38.162,-16.067 cw(c-31.71,-13.256) -38.746,-13.118 cw(c-31.991,-13.284) -38.004,-10.201 cw(c-31.697,-13.397) -36.096,-7.861 cw(c-31.904,-13.187) -33.364,-6.569 cw(c-31.801,-13.498) -30.333,-6.548 cw(c-31.767,-13.193) -27.584,-7.834 cw(c-31.949,-13.48) -25.629,-10.166 cw(c-31.68,-13.308) -24.864,-13.115 cw(c-32.029,-13.35) -25.417,-16.12 cw(c-31.715,-13.454) -27.209,-18.599 cw(c-31.978,-13.203) -29.888,-20.094 cw(c-31.834,-13.647) -31.408,-20.368 cw(c-31.847,-13.333) -32.952,-20.294 cw(c-31.828,-13.149) -35.823,-19.179 cw(c-32.079,-13.544) -37.008,-18.178 cw(c-31.854,-13.342) -37.939,-16.937 cw(c-31.689,-13.234) -38.913,-14.002 cw(c-32.153,-13.29) -38.898,-12.445 cw(c-31.867,-13.335) -38.533,-10.93 cw(c-31.666,-13.398) -36.886,-8.299 cw(c-32.005,-13.077) -35.672,-7.314 cw(c-31.865,-13.313) -34.267,-6.627 cw(c-31.774,-13.553) -32.744,-6.256 cw(c-31.784,-13.441) -31.177,-6.217 cw(c-31.749,-13.058) -29.639,-6.526 cw(c-31.839,-13.301) -28.207,-7.173 cw(c-31.97,-13.531) -26.947,-8.114 cw(c-31.896,-13.459) -25.914,-9.302 cw(c-31.577,-13.24) -25.168,-10.689 cw(c-31.807,-13.32) -24.753,-12.21 cw(c-32.077,-13.367) -24.674,-13.787 cw(c-31.982,-13.377) -24.932,-15.346 cw(c-31.611,-13.484) -25.528,-16.811 cw(c-31.803,-13.365) -26.438,-18.105 cw(c-32.018,-13.181) -27.608,-19.176 cw(c-31.97,-13.254) -28.979,-19.973 cw(c-31.816,-13.608) -30.493,-20.45 cw(c-31.842,-13.401) -32.077,-20.574 cw(c-31.838,-13.11) -33.653,-20.354 cw(c-31.862,-13.184) -35.148,-19.804 cw(c-32.035,-13.528) -36.486,-18.938 cw(c-31.904,-13.391) -37.595,-17.792 cw(c-31.67,-13.204) -38.433,-16.432 cw(c-31.735,-13.229) -38.964,-14.924 cw(c-32.108,-13.313) -39.15,-13.335 cw(c-31.938,-13.328) -38.974,-11.744 cw(c-31.637,-13.391) -38.458,-10.225 cw(c-31.689,-13.361) -37.631,-8.85 cw(c-31.991,-13.128) -36.522,-7.689 cw(c-31.907,-13.254) -35.178,-6.807 cw(c-31.759,-13.533) -33.673,-6.235 cw(c-31.767,-13.482) -32.08,-5.995 cw(c-31.779,-13.105) -30.472,-6.109 cw(c-31.82,-13.229) -28.93,-6.584 cw(c-31.945,-13.529) -27.525,-7.382 cw(c-31.916,-13.498) -26.32,-8.461 cw(c-31.635,-13.25) -25.38,-9.778 cw(c-31.739,-13.288) -24.76,-11.274 cw(c-32.057,-13.384) -24.479,-12.872 cw(c-32.024,-13.387) -24.543,-14.494 cw(c-31.658,-13.445) -24.959,-16.063 cw(c-31.733,-13.397) -25.72,-17.5 cw(c-32.017,-13.208) -26.775,-18.74 cw(c-32.005,-13.229) -28.071,-19.728 cw(c-31.818,-13.545) -29.552,-20.411 cw(c-31.821,-13.477) -31.149,-20.742 cw(c-31.858,-13.129) -32.784,-20.719 cw(c-31.865,-13.143) -34.377,-20.349 cw(c-31.988,-13.484) -35.852,-19.64 cw(c-31.949,-13.457) -37.131,-18.617 cw(c-31.699,-13.201) -38.158,-17.338 cw(c-31.706,-13.2) -38.891,-15.868 cw(c-32.043,-13.32) -39.287,-14.274 cw(c-32.019,-13.336) -39.314,-12.631 cw(c-31.655,-13.367) -38.982,-11.018 cw(c-31.649,-13.363) -38.315,-9.511 cw(c-31.952,-13.183) -37.335,-8.184 cw(c-31.966,-13.196) -36.081,-7.112 cw(c-31.753,-13.503) -34.621,-6.337 cw(c-31.743,-13.513) -33.029,-5.889 cw(c-31.797,-13.17) -31.376,-5.798 cw(c-31.814,-13.145) -29.744,-6.082 cw(c-31.917,-13.512) -28.211,-6.715 cw(c-31.923,-13.535) -26.846,-7.661 cw(c-31.697,-13.28) -25.718,-8.88 cw(c-31.67,-13.237) -24.894,-10.323 cw(c-32.025,-13.394) -24.403,-11.914 cw(c-32.057,-13.406) -24.261,-13.575 cw(c-31.721,-13.418) -24.482,-15.227 cw(c-31.649,-13.417) -25.07,-16.789 cw(c-32.003,-13.24) -25.987,-18.186 cw(c-32.04,-13.217) -27.18,-19.358 cw(c-31.838,-13.479) -28.599,-20.244 cw(c-31.782,-13.555) -30.184,-20.788 cw(c-31.873,-13.162) -31.851,-20.973 cw(c-31.879,-13.11) -33.521,-20.8 cw(c-31.951,-13.426) -35.114,-20.269 cw(c-31.984,-13.538) -36.548,-19.393 cw(c-31.735,-13.212) -37.757,-18.222 cw(c-31.69,-13.168) -38.692,-16.819 cw(c-31.975,-13.311) -39.301,-15.248 cw(c-32.104,-13.362) -39.54,-13.578 cw(c-31.688,-13.346) -39.408,-11.893 cw(c-31.616,-13.354) -38.921,-10.274 cw(c-31.902,-13.229) -38.096,-8.797 cw(c-32.041,-13.149) -36.958,-7.543 cw(c-31.76,-13.463) -35.571,-6.568 cw(c-31.715,-13.532) -34.007,-5.909 cw(c-31.799,-13.238) -32.337,-5.603 cw(c-31.827,-13.058) -30.639,-5.68 cw(c-31.891,-13.48) -28.998,-6.129 cw(c-31.919,-13.568) -27.488,-6.917 cw(c-31.749,-13.322) -26.182,-8.012 cw(c-31.612,-13.171) -25.156,-9.375 cw(c-31.983,-13.393) -24.453,-10.931 cw(c-32.078,-13.43) -24.097,-12.603 cw(c-31.786,-13.405) -24.109,-14.313 cw(c-31.562,-13.418) -24.505,-15.978 cw(c-31.973,-13.273) -25.26,-17.517 cw(c-32.071,-13.217) -26.325,-18.863 cw(c-31.871,-13.421) -27.655,-19.947 cw(c-31.728,-13.62) -29.196,-20.706 cw(c-31.878,-13.207) -30.868,-21.107 cw(c-31.899,-13.087) -32.59,-21.144 cw(c-31.928,-13.364) -34.279,-20.809 cw(c-31.997,-13.619) -35.852,-20.103 cw(c-31.774,-13.239) -37.232,-19.067 cw(c-31.775,-13.213) -39.184,-16.238 cw(c-32.172,-13.404) -39.644,-14.57 cw(c-31.735,-13.334) -39.725,-12.84 cw(c-31.702,-13.318) -38.786,-9.522 cw(c-32.115,-13.125) -37.792,-8.098 cw(c-31.782,-13.418) -36.505,-6.929 cw(c-31.741,-13.446) -33.339,-5.533 cw(c-31.857,-12.99) -31.602,-5.391 cw(c-31.87,-13.433) -29.875,-5.638 cw(c-31.869,-13.496) -26.77,-7.194 cw(c-31.617,-13.144) -25.548,-8.446 cw(c-31.939,-13.398) -24.632,-9.938 v2@-23.229,-11.341
  Top Layer w0.7: v2(-21.488,-15.85) -20.843,-15.204 -20.843,-14.214 -20.826,-14.214 ; v2(-21.336,-11.176) -21.336,-11.215 -20.826,-11.725 -20.826,-12.964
